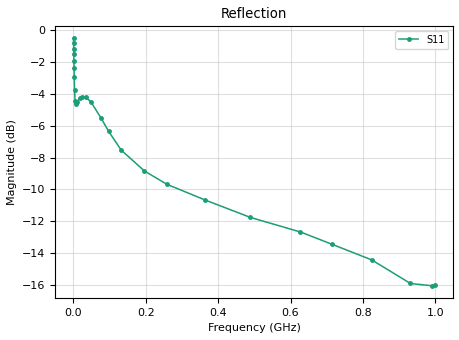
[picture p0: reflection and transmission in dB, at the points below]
! HEWLETT PACKARD,8753C,0,4.13
! 22 May 2016  22:26:10
! frequency  re(S11)  im(S11)
# Hz  S RI R 50
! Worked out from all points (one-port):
!   1601 points, 300 kHz to 1 GHz, reference 50 ohm
!   lowest |S11| = -16.1 dB at 989.9 MHz (marker M1), VSWR 1.37, Z = 49.8 + j15.9 ohm
!   |S11| at or under -10 dB: 285.6 MHz to end of sweep
!   S11 on the Smith chart (normalised r, x): 300 kHz: 0.03, +0.14; 1.43 MHz: 0.14, +0.57; 4.542 MHz: 0.81, +1.34; 34.17 MHz: 3.82, -1.17; 258.3 MHz: 0.80, -0.58; 1 GHz: 1.01, +0.32
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300000  -0.9073 0.26
526648  -0.8186 0.399
831156  -0.6854 0.5409
1070959  -0.571 0.6216
1429799  -0.4014 0.6956
1814510  -0.2347 0.7246
2291092  -0.0684 0.709
3121421  0.1198 0.6387
4542400  0.2882 0.5274
6315422  0.3976 0.4341
1.04323e7  0.5246 0.2849
1.740854e7  0.5993 0.1265
2.482494e7  0.6183 0.0122
3.416656e7  0.6082 -0.095
4.79868e7  0.5591 -0.2084
7.689335e7  0.4187 -0.323
9.758292e7  0.3315 -0.3482
1.322763e8  0.222 -0.3564
1.964364e8  0.09 -0.3497
2.582972e8  -0.00745 -0.3279
3.646208e8  -0.1403 -0.2567
4.892663e8  -0.2238 -0.1283
6.272395e8  -0.2314 0.0199
7.156166e8  -0.1889 0.0967
8.247674e8  -0.1085 0.1555
9.314815e8  -0.0178 0.1589
9.899105e8  0.0228 0.1557
1e9  0.0314 0.1547
